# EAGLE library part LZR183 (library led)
LED BLOCK 3 LEDs, Siemens

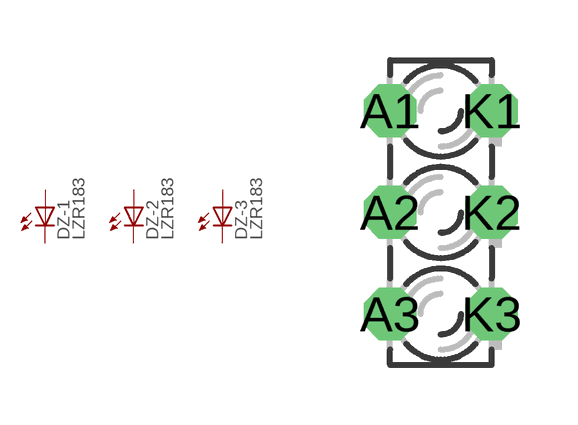
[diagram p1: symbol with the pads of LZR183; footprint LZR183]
Designator prefix DZ; gates -1=LED -2=LED -3=LED

## LZR183  [LZR183]
A1  -1:A  pas
A2  -2:A  pas
A3  -3:A  pas
K1  -1:C  pas
K2  -2:C  pas
K3  -3:C  pas

## Footprint LZR183 (pad centres in mm)
LED BLOCK 3 LEDs, Siemens
drill 0.813 octagon: A1 -1.27,2.54; A2 -1.27,0; A3 -1.27,-2.54; K1 1.27,2.54; K2 1.27,0; K3 1.27,-2.54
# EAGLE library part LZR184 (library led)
LED BLOCK 4 LEDs, Siemens

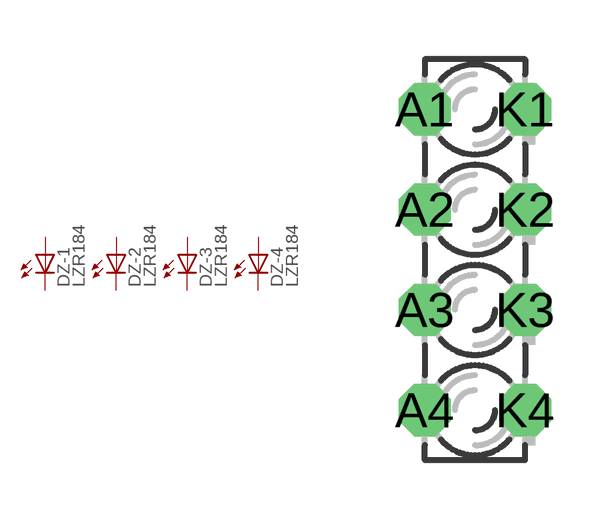
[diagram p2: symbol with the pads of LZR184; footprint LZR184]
Designator prefix DZ; gates -1=LED -2=LED -3=LED -4=LED

## LZR184  [LZR184]
A1  -1:A  pas
A2  -2:A  pas
A3  -3:A  pas
A4  -4:A  pas
K1  -1:C  pas
K2  -2:C  pas
K3  -3:C  pas
K4  -4:C  pas

## Footprint LZR184 (pad centres in mm)
LED BLOCK 4 LEDs, Siemens
drill 0.813 octagon: A1 -1.27,3.81; A2 -1.27,1.27; A3 -1.27,-1.27; A4 -1.27,-3.81; K1 1.27,3.81; K2 1.27,1.27; K3 1.27,-1.27; K4 1.27,-3.81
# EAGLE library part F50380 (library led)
Z-POWER LED Source: www.zpowerled.com .. F50380.pdf

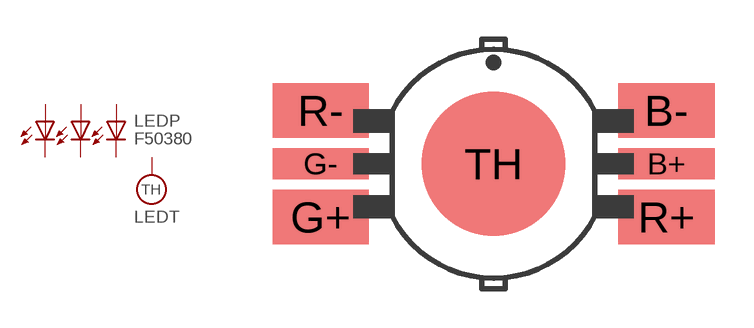
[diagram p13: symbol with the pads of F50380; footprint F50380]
Designator prefix LED; gates P=F50380 T=THERMAL

## F50380  [F50380]
B+  P:B+  pas
B-  P:B-  pas
G+  P:G+  pas
G-  P:G-  pas
R+  P:R+  pas
R-  P:R-  pas
TH  T:TH  pas

## Footprint F50380 (pad centres in mm)
Z-POWER LED Source: www.zpowerled.com .. F50380.pdf
smd 3.7 x 1.2: B+ 6.65,0; G- -6.65,0
smd 3.7 x 2.1: B- 6.65,2.05; G+ -6.65,-2.05; R+ 6.65,-2.05; R- -6.65,2.05
smd 5.55 x 5.55: TH 0,0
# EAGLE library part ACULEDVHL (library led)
ACULED® VHL Standard Monochromatic and Multi-Colored Four-Chip LED Source: http://optoelectronics.perkinelmer.com/content/Datasheets/DTS_ACULEDVHL.pdf

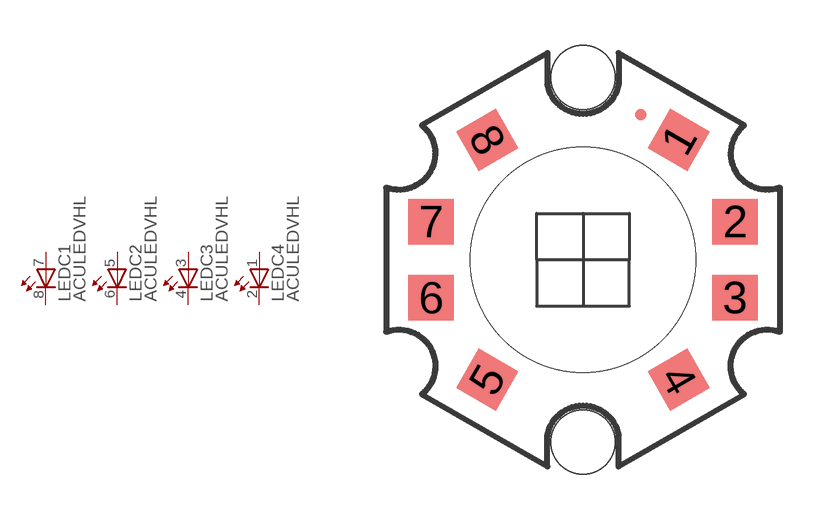
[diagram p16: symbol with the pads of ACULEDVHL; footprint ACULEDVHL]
Designator prefix LED; gates C1=LED-PAD C2=LED-PAD C3=LED-PAD C4=LED-PAD

## ACULEDVHL-RGBY  [ACULEDVHL]
1  C4:A  pas
2  C4:C  pas
3  C3:A  pas
4  C3:C  pas
5  C2:A  pas
6  C2:C  pas
7  C1:A  pas
8  C1:C  pas

## ACULEDVHL-IR  [ACULEDVHL]
1  C4:C  pas
2  C4:A  pas
3  C3:C  pas
4  C3:A  pas
5  C2:C  pas
6  C2:A  pas
7  C1:C  pas
8  C1:A  pas

## Footprint ACULEDVHL (pad centres in mm)
ACULED® VHL Standard Monochromatic and Multi-Colored Four-Chip LED Source: http://optoelectronics.perkinelmer.com/content/Datasheets/DTS_ACULEDVHL.pdf
smd 1.5 x 1.5 rotated 60: 1 3.15,3.95
smd 1.5 x 1.5: 2 5,1.25; 3 5,-1.25; 6 -5,-1.25; 7 -5,1.25
smd 1.5 x 1.5 rotated 300: 4 3.15,-3.95
smd 1.5 x 1.5 rotated 240: 5 -3.15,-3.95
smd 1.5 x 1.5 rotated 120: 8 -3.15,3.95
hole 2.1 at 0,6
hole 2.1 at 0,-6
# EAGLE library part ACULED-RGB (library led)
ACULED Source: http://optoelectronics.perkinelmer.com/content/Datasheets/DTS_ACULED.pdf

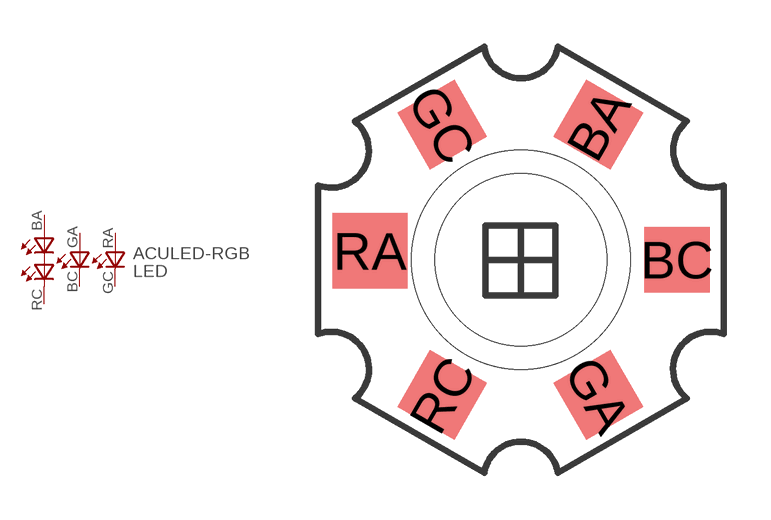
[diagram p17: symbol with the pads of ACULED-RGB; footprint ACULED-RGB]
Designator prefix LED

## ACULED-RGB  [ACULED-RGB]
BA  GA  pas
BC  BC  pas
GA  BA  pas
GC  RC  pas
RA  RA  pas
RC  GC  pas

## Footprint ACULED-RGB (pad centres in mm)
ACULED Source: http://optoelectronics.perkinelmer.com/content/Datasheets/DTS_ACULED.pdf
smd 2.1 x 2.1 rotated 60: BA 2.468,4.319
smd 2.1 x 2.1: BC 4.983,0
smd 2.1 x 2.1 rotated 300: GA 2.468,-4.319
smd 2.1 x 2.1 rotated 120: GC -2.515,4.319
smd 2.4 x 2.4: RA -4.825,0.285
smd 2.1 x 2.1 rotated 240: RC -2.515,-4.319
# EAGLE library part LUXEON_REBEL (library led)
LUXEON Rebel Display layer 93, Pins, and connect all contact points with a net. The thermal pads are defined in a separate gate with addlevel REQUEST. Draw a net named 'TH' and connect all thermal pads with it. Please read the Package's Description about DRC settings. Source: http://www.lumileds.com/pdfs/AB32.pdf

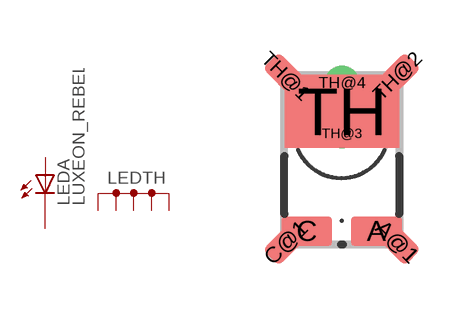
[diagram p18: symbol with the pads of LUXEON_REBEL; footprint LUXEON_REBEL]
Designator prefix LED; gates A=LED-A2C2 TH=LUXEON_THERMAL

## LUXEON_REBEL  [LUXEON_REBEL]
A  A:A  pas
A@1  A:A  pas
C  A:C  pas
C@1  A:C  pas
TH  TH:TH  pwr
TH@1  TH:TH  pwr
TH@2  TH:TH  pwr
TH@3  TH:TH  pwr
TH@4  TH:TH  pwr

## Footprint LUXEON_REBEL (pad centres in mm)
LUXEON® Rebel LED Set DRC - Clearance - Same Signals to 0 to avoid DRC error message for Pad in SMD. Please read the Device's Description how to connect it correctly in the Schematic. Source: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
smd 1.26 x 0.73: A 0.87,-2.51; C -0.87,-2.51
smd 1.1 x 0.57 rotated 315: A@1 1.39,-2.78
smd 1.1 x 0.57 rotated 225: C@1 -1.39,-2.79
smd 2.86 x 1.83: TH 0.01,0.49
smd 1.1 x 0.57 rotated 135: TH@1 -1.39,1.37
smd 1.1 x 0.57 rotated 45: TH@2 1.39,1.38
drill 0.25 pad 0.35: TH@3 0.01,-0.06
drill 0.35 pad 0.5: TH@4 0.01,1.2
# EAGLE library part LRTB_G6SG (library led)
LRTB G6SG 6-lead TOPLED® Source: OSRAM Opto Semiconductors ... LRTB_G6SG_Pb_free.pdf

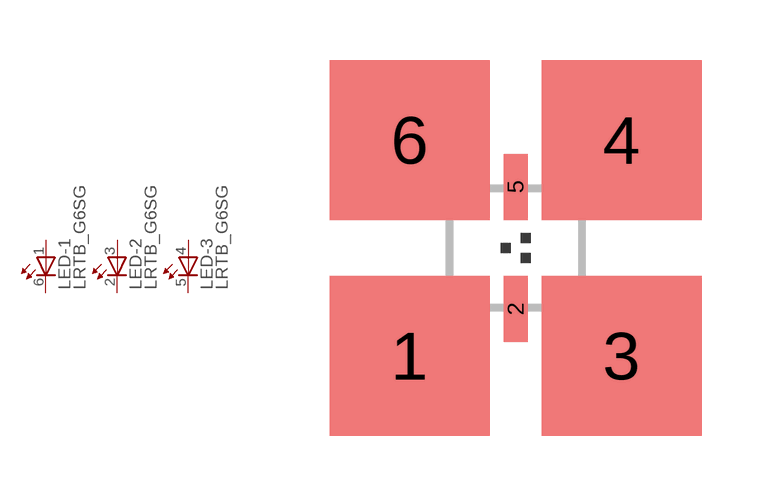
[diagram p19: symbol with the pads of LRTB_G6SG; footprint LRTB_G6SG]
Designator prefix LED; gates -1=LED-PAD -2=LED-PAD -3=LED-PAD

## LRTB_G6SG  [LRTB_G6SG]
1  -1:A  pas
2  -2:C  pas
3  -2:A  pas
4  -3:A  pas
5  -3:C  pas
6  -1:C  pas

## Footprint LRTB_G6SG (pad centres in mm)
LRTB G6SG 6-lead TOPLED® Source: OSRAM Opto Semiconductors ... LRTB_G6SG_Pb_free.pdf
smd 4 x 4: 1 -2.65,-2.7; 3 2.65,-2.7; 4 2.65,2.7; 6 -2.65,2.7
smd 0.6 x 1.65: 2 0,-1.525; 5 0,1.525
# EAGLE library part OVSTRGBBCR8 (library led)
Full Color PLCC6 LED OVSTRGBBCR8 Source: www.optekinc.com .. ovstrgbbcr8.pdf

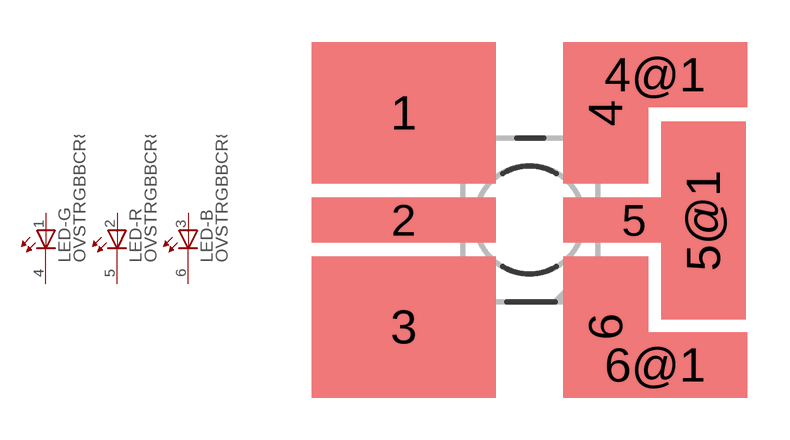
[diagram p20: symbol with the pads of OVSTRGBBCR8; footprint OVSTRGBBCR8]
Designator prefix LED; gates -G=LED-PAD-2K -R=LED-PAD-2K -B=LED-PAD-2K

## OVSTRGBBCR8  [OVSTRGBBCR8]
1  -G:A  pas
2  -R:A  pas
3  -B:A  pas
4  -G:C  pas
4@1  -G:C  pas
5  -R:C  pas
5@1  -R:C  pas
6  -B:C  pas
6@1  -B:C  pas

## Footprint OVSTRGBBCR8 (pad centres in mm)
Full Color PLCC6 LED OVSTRGBBCR8 Source: www.optekinc.com .. ovstrgbbcr8.pdf
smd 6.5 x 5: 1 -4.442,3.786; 3 -4.442,-3.786
smd 6.5 x 1.6: 2 -4.442,0
smd 3 x 5: 4 2.692,3.786; 6 2.692,-3.786
smd 6.5 x 2.3: 4@1 4.442,5.136; 6@1 4.442,-5.136
smd 5 x 1.6: 5 3.692,0
smd 3 x 7: 5@1 6.15,-0.025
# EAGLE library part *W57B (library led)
Golden Dragon® 1 Watt LED Place heat sink pads of cathode with INVOKE Source: www.osram-os.com la_ly_w57b.pdf

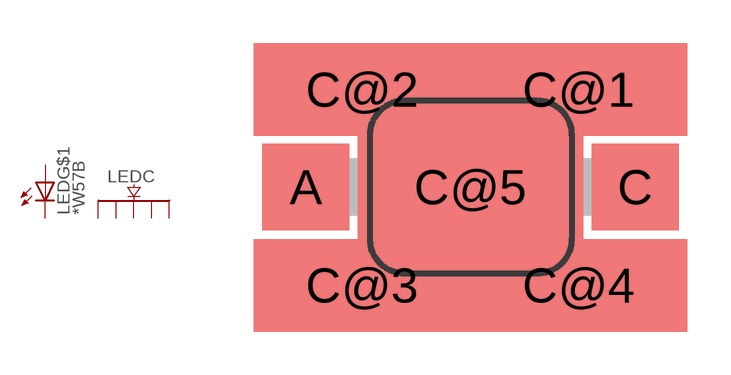
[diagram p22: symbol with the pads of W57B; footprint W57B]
Designator prefix LED; gates G$1=LED C=DRAGON-5C

## LAW57B, LYW57B  [W57B]
A  G$1:A  pas
C  G$1:C  pas
C@1  C:C  pas
C@2  C:C  pas
C@3  C:C  pas
C@4  C:C  pas
C@5  C:C  pas

## Footprint W57B (pad centres in mm)
Golden Dragon® 1 Watt LED Source: OSRAM la_ly_w57b.pdf
smd 3 x 3: A -5.7,0; C 5.7,0
smd 7.5 x 3.2: C@1 3.75,3.375; C@2 -3.75,3.375; C@3 -3.75,-3.4; C@4 3.75,-3.4
smd 7.8 x 4: C@5 0,0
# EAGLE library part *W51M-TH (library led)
Golden DRAGON® with Lens Enhanced Thinfilm LED Source: LA_LR_LY_W51M_Pb_free[1].pdf

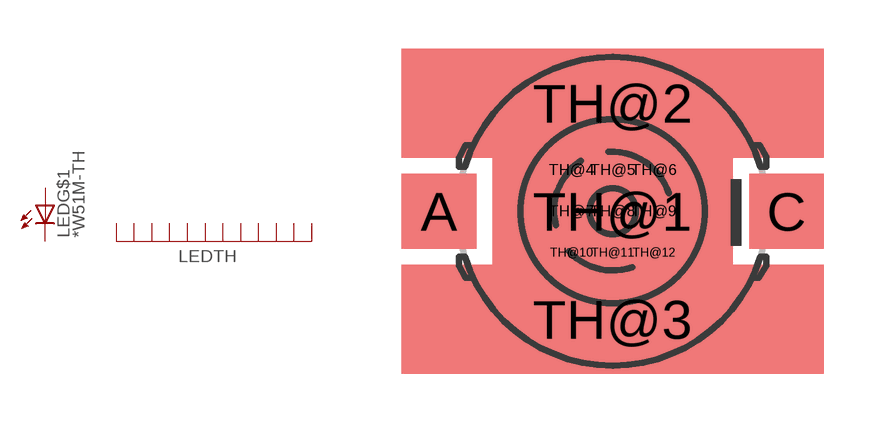
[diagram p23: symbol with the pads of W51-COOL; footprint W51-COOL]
Designator prefix LED; gates G$1=LED TH=THERMAL-12

## LAW51M-TH, LRW51M-TH, LYW51M-TH  [W51-COOL]
A  G$1:A  pas
C  G$1:C  pas
TH@1  TH:TH1  pas
TH@2  TH:TH2  pas
TH@3  TH:TH3  pas
TH@4  TH:TH4  pas
TH@5  TH:TH5  pas
TH@6  TH:TH6  pas
TH@7  TH:TH7  pas
TH@8  TH:TH8  pas
TH@9  TH:TH9  pas
TH@10  TH:TH10  pas
TH@11  TH:TH11  pas
TH@12  TH:TH12  pas

## Footprint W51-COOL (pad centres in mm)
Golden DRAGON® with Lens Enhanced Thinfilm LED with thermal holes Source: LA_LR_LY_W51M_Pb_free[1].pdf
smd 2.3 x 2.3: A -5.35,0; C 5.35,0
smd 7.4 x 3.4: TH@1 0,0
smd 13 x 3.35: TH@2 0,3.325; TH@3 0,-3.325
drill 0.5 pad 0.9 square: TH@4 -1.27,1.27; TH@5 0,1.27; TH@6 1.27,1.27; TH@7 -1.27,0; TH@8 0,0; TH@9 1.27,0; TH@10 -1.27,-1.27; TH@11 0,-1.27; TH@12 1.27,-1.27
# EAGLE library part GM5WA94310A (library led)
Chip LED RGB Source: http://document.sharpsma.com/files/GM5WA94310A_SS.pdf

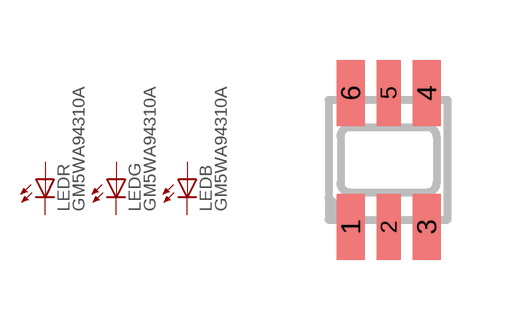
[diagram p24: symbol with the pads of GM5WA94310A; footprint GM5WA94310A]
Designator prefix LED; gates R=LED G=LED B=LED

## GM5WA94310A  [GM5WA94310A]
1  B:A  pas
2  R:A  pas
3  G:A  pas
4  G:C  pas
5  R:C  pas
6  B:C  pas

## Footprint GM5WA94310A (pad centres in mm)
Chip LED RGB Source: http://document.sharpsma.com/files/GM5WA94310A_SS.pdf
smd 0.7 x 1.65: 1 -0.95,-1.675; 3 0.95,-1.675; 4 0.95,1.675; 6 -0.95,1.675
smd 0.6 x 1.65: 2 0,-1.675; 5 0,1.675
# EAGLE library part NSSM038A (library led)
NICHIA CHIP TYPE FULL COLOR LED Switch on Layer 93 and connect all Contact-Refs with NET please note ERC warnings Not connected INPUT-Pin xx Set DRC Clearance - Same Signals - Smd | Smd, 0mm Source: NICIA CORPORATION .. NSSM038AT-E.PDF

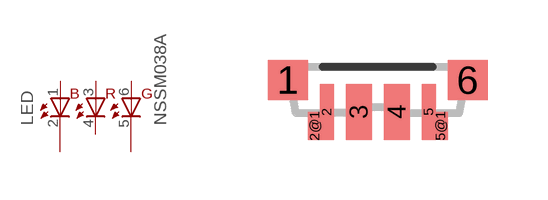
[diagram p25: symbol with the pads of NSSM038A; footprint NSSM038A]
Designator prefix LED

## NSSM038A  [NSSM038A]
1  BA  pas
2  BC  pas
2@1  BC  pas
3  RA  pas
4  RC  pas
5  GC  pas
5@1  GC  pas
6  GA  pas

## Footprint NSSM038A (pad centres in mm)
3 LED (RGB) package Set DRC Clearance - Same Signals - Smd | Smd, 0mm Source: NICIA CORPORATION .. NSSM038AT-E.PDF
smd 1 x 1: 1 -2.25,-0.5; 6 2.25,-0.5
smd 0.35 x 1.4: 2 -1.275,-1.3; 5 1.275,-1.3
smd 0.35 x 0.7: 2@1 -1.575,-1.65; 5@1 1.575,-1.65
smd 0.65 x 1.4: 3 -0.475,-1.3; 4 0.475,-1.3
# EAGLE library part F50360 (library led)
Full color Z-Power LED RGB P5-II Series Source: http://www.seoulsemicon.co.kr .. F50360.pdf

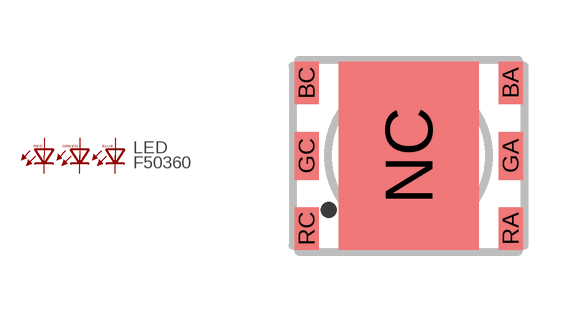
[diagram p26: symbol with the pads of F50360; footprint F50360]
Designator prefix LED

## F50360  [F50360]
BA  BA  pas
BC  BC  pas
GA  GA  pas
GC  GC  pas
RA  RA  pas
RC  RC  pas

## Footprint F50360 (pad centres in mm)
Full color Z-Power LED RGB Source: http://www.seoulsemicon.co.kr .. F50360.pdf
smd 0.6 x 1.05: BA 2.55,1.825; BC -2.55,1.825; RA 2.55,-1.825; RC -2.55,-1.825
smd 0.6 x 1.2: GA 2.55,0; GC -2.55,0
smd 3.5 x 4.7: NC 0,0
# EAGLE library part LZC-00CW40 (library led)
High Luminous Efficacy Cool White LED Emitter Source: http://www.ledengin.com/products/40wLZ/LZC-00CW40.pdf

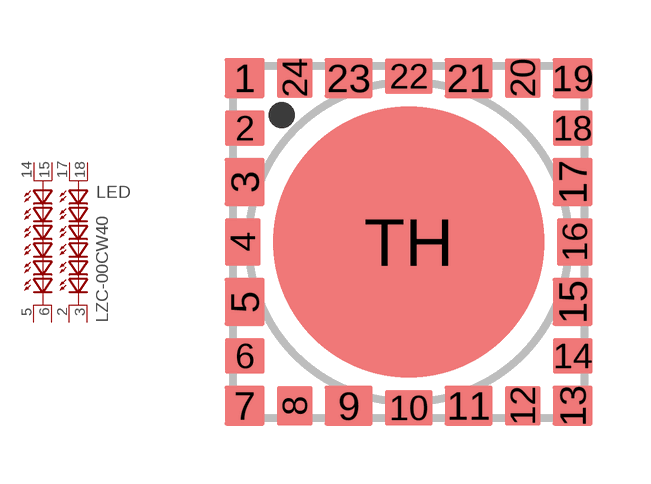
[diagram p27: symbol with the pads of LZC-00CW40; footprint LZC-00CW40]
Designator prefix LED

## LZC-00CW40  [LZC-00CW40]
2  C4  pas
3  C3  pas
5  C2  pas
6  C1  pas
14  A2  pas
15  A1  pas
17  A4  pas
18  A3  pas

## Footprint LZC-00CW40 (pad centres in mm)
High Luminous Efficacy LED Emitter Source: http://www.ledengin.com/products/40wLZ/LZC-00CW40.pdf
smd 1 x 1: 1 -4.1,4.1; 7 -4.1,-4.1; 13 4.1,-4.1; 19 4.1,4.1
smd 1 x 0.9: 2 -4.1,2.85; 6 -4.1,-2.85; 14 4.1,-2.85; 18 4.1,2.85
smd 1 x 1.2: 3 -4.1,1.5; 5 -4.1,-1.5; 15 4.1,-1.5; 17 4.1,1.5
smd 0.9 x 1.2: 4 -4.15,0; 16 4.15,0
smd 0.9 x 1: 8 -2.85,-4.1; 12 2.85,-4.1; 20 2.85,4.1; 24 -2.85,4.1
smd 1.2 x 1: 9 -1.5,-4.1; 11 1.5,-4.1; 21 1.5,4.1; 23 -1.5,4.1
smd 1.2 x 0.9: 10 0,-4.15; 22 0,4.15
smd 6.8 x 6.8: TH 0,0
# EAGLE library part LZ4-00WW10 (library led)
High Luminous Efficacy 10W LED http://www.ledengin.com/products/10wLZ/LZ4-00WW10.pdf

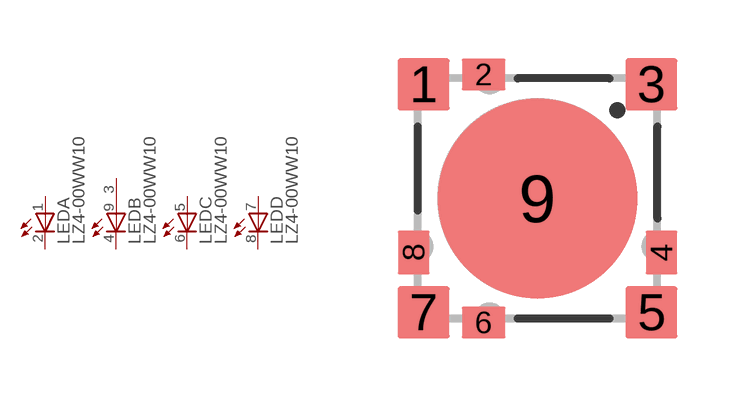
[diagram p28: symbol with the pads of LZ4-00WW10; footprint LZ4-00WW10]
Designator prefix LED; gates B=LED-A2 C=LED-A D=LED-A A=LED-A

## LZ4-00WW10  [LZ4-00WW10]
1  A:A  pas
2  A:C  pas
3  B:A  pas
4  B:C  pas
5  C:A  pas
6  C:C  pas
7  D:A  pas
8  D:C  pas
9  B:A  pas

## Footprint LZ4-00WW10 (pad centres in mm)
High Luminous Efficacy 10W LED Source: http://www.ledengin.com/products/10wLZ/LZ4-00WW10.pdf
smd 1.3 x 1.3: 1 -2.85,2.85; 3 2.85,2.85; 5 2.85,-2.85; 7 -2.85,-2.85
smd 1.1 x 0.8: 2 -1.35,3.1; 6 -1.35,-3.1
smd 0.8 x 1.1: 4 3.1,-1.35; 8 -3.1,-1.35
smd 5 x 5: 9 0,0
